VERSION 5.7 ;
  NOWIREEXTENSIONATPIN ON ;
  DIVIDERCHAR "/" ;
  BUSBITCHARS "[]" ;
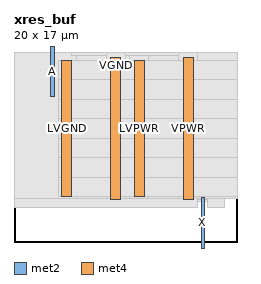
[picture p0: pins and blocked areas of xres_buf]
MACRO xres_buf
  CLASS BLOCK ;
  FOREIGN xres_buf ;
  ORIGIN 0.000 0.000 ;
  SIZE 20.000 BY 17.000 ;
  PIN A
    DIRECTION INPUT ;
    USE SIGNAL ;
    ANTENNAGATEAREA 1.027200 ;
    ANTENNADIFFAREA 0.607200 ;
    PORT
      LAYER met2 ;
        RECT 3.300 13.000 3.580 20.115 ;
    END
  END A
  PIN X
    DIRECTION OUTPUT TRISTATE ;
    USE SIGNAL ;
    ANTENNADIFFAREA 0.492900 ;
    PORT
      LAYER met2 ;
        RECT 16.740 -2.000 17.020 4.000 ;
    END
  END X
  PIN VPWR
    DIRECTION INOUT ;
    USE POWER ;
    PORT
      LAYER met4 ;
        RECT 15.150 3.815 16.050 16.535 ;
    END
  END VPWR
  PIN VGND
    DIRECTION INOUT ;
    USE GROUND ;
    PORT
      LAYER met4 ;
        RECT 8.650 3.815 9.550 16.535 ;
    END
  END VGND
  PIN LVPWR
    DIRECTION INOUT ;
    USE POWER ;
    ANTENNADIFFAREA 1.176500 ;
    PORT
      LAYER met4 ;
        RECT 10.750 4.070 11.650 16.280 ;
    END
  END LVPWR
  PIN LVGND
    DIRECTION INOUT ;
    USE GROUND ;
    PORT
      LAYER met4 ;
        RECT 4.250 4.070 5.150 16.280 ;
    END
  END LVGND
  OBS
      LAYER nwell ;
        RECT 2.390 3.655 17.930 16.495 ;
      LAYER li1 ;
        RECT 2.720 3.985 17.600 16.365 ;
      LAYER met1 ;
        RECT 2.720 3.815 17.600 16.535 ;
      LAYER met2 ;
        RECT 0.000 12.720 3.020 17.000 ;
        RECT 3.860 12.720 18.870 17.000 ;
        RECT 0.000 4.280 18.870 12.720 ;
        RECT 0.000 3.065 16.460 4.280 ;
        RECT 17.300 3.065 18.870 4.280 ;
      LAYER met3 ;
        RECT 0.000 3.905 20.000 17.000 ;
      LAYER met4 ;
        RECT 5.150 16.935 20.000 17.000 ;
        RECT 5.150 16.680 8.250 16.935 ;
        RECT 5.550 3.900 8.250 16.680 ;
        RECT 9.950 16.680 14.750 16.935 ;
        RECT 9.950 3.900 10.350 16.680 ;
        RECT 12.050 3.900 14.750 16.680 ;
        RECT 16.450 14.485 20.000 16.935 ;
        RECT 16.450 3.900 20.000 14.485 ;
      LAYER met5 ;
        RECT 4.025 14.575 20.000 16.235 ;
        RECT 4.025 12.735 20.000 14.575 ;
        RECT 4.025 11.075 20.000 12.735 ;
        RECT 4.025 9.235 20.000 11.075 ;
        RECT 4.025 7.575 20.000 9.235 ;
        RECT 4.025 5.735 20.000 7.575 ;
        RECT 4.025 4.075 20.000 5.735 ;
  END
END xres_buf
END LIBRARY
